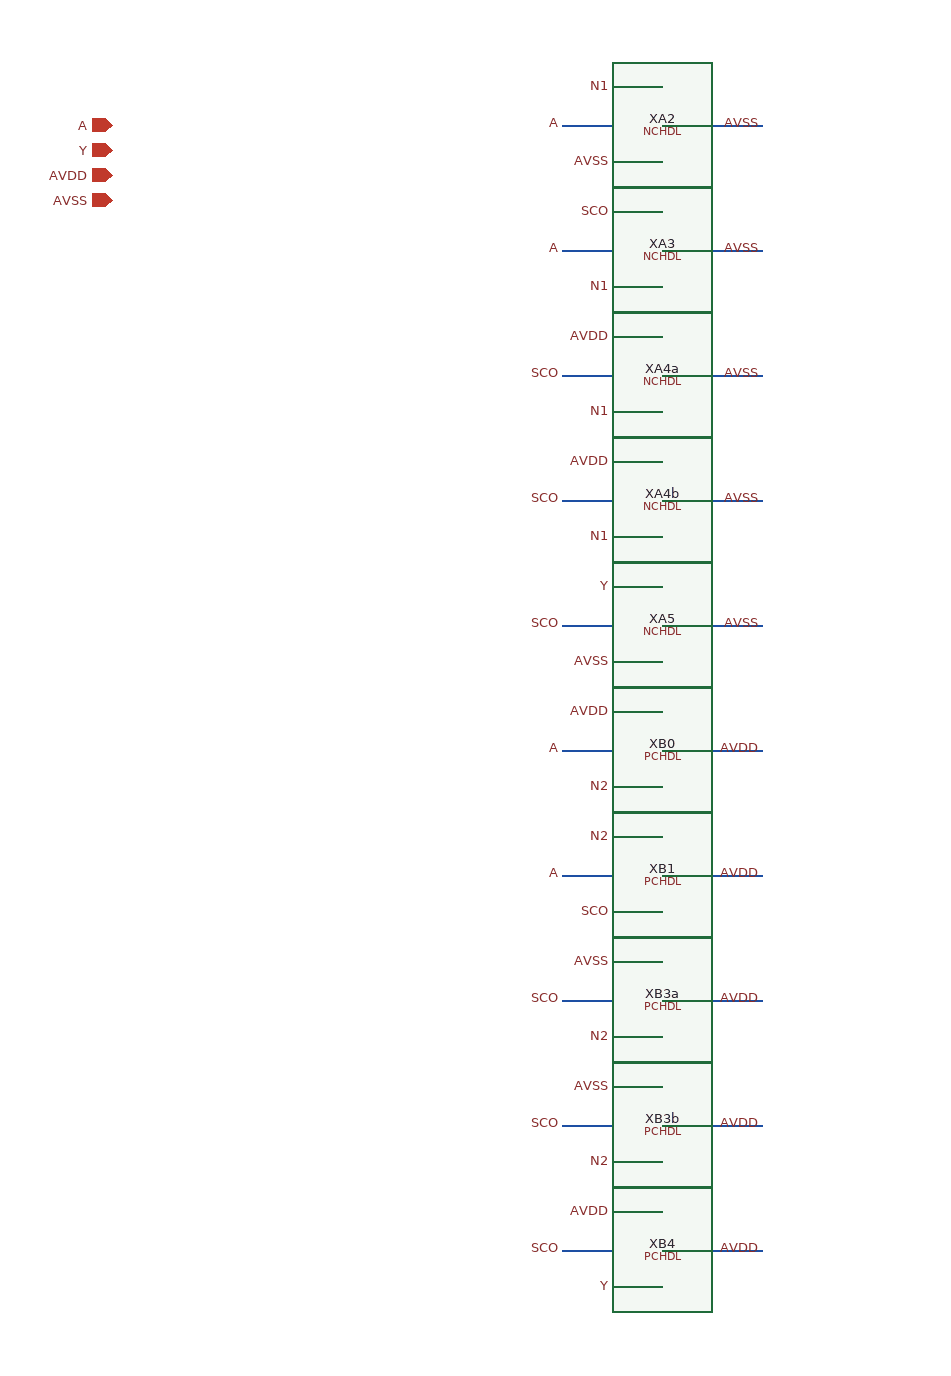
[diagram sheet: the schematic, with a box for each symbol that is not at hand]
v {xschem version=3.0.0 file_version=1.2 }
C {devices/iopin.sym} 0 0 0 0{name=p0 lab=A}
C {devices/iopin.sym} 0 20 0 0{name=p1 lab=Y}
C {devices/iopin.sym} 0 40 0 0{name=p2 lab=AVDD}
C {devices/iopin.sym} 0 60 0 0{name=p3 lab=AVSS}
C {SUN_TR_SK130NM/NCHDL.sym} 400 0 0 0 {name=XA2}
N 400.0 -30.0 440.0 -30.0{lab=N1}
C {devices/lab_pin.sym} 400.0 -30.0 0 0  {name=l0 sig_type=std_logic lab=N1 }
N 360.0 0.0 400.0 0.0{lab=A}
C {devices/lab_pin.sym} 360.0 0.0 0 0  {name=l1 sig_type=std_logic lab=A }
N 400.0 30.0 440.0 30.0{lab=AVSS}
C {devices/lab_pin.sym} 400.0 30.0 0 0  {name=l2 sig_type=std_logic lab=AVSS }
N 520.0 0.0 440.0 0.0{lab=AVSS}
C {devices/lab_pin.sym} 520.0 0.0 0 0  {name=l3 sig_type=std_logic lab=AVSS }
C {SUN_TR_SK130NM/NCHDL.sym} 400 100 0 0 {name=XA3}
N 400.0 70.0 440.0 70.0{lab=SCO}
C {devices/lab_pin.sym} 400.0 70.0 0 0  {name=l4 sig_type=std_logic lab=SCO }
N 360.0 100.0 400.0 100.0{lab=A}
C {devices/lab_pin.sym} 360.0 100.0 0 0  {name=l5 sig_type=std_logic lab=A }
N 400.0 130.0 440.0 130.0{lab=N1}
C {devices/lab_pin.sym} 400.0 130.0 0 0  {name=l6 sig_type=std_logic lab=N1 }
N 520.0 100.0 440.0 100.0{lab=AVSS}
C {devices/lab_pin.sym} 520.0 100.0 0 0  {name=l7 sig_type=std_logic lab=AVSS }
C {SUN_TR_SK130NM/NCHDL.sym} 400 200 0 0 {name=XA4a}
N 400.0 170.0 440.0 170.0{lab=AVDD}
C {devices/lab_pin.sym} 400.0 170.0 0 0  {name=l8 sig_type=std_logic lab=AVDD }
N 360.0 200.0 400.0 200.0{lab=SCO}
C {devices/lab_pin.sym} 360.0 200.0 0 0  {name=l9 sig_type=std_logic lab=SCO }
N 400.0 230.0 440.0 230.0{lab=N1}
C {devices/lab_pin.sym} 400.0 230.0 0 0  {name=l10 sig_type=std_logic lab=N1 }
N 520.0 200.0 440.0 200.0{lab=AVSS}
C {devices/lab_pin.sym} 520.0 200.0 0 0  {name=l11 sig_type=std_logic lab=AVSS }
C {SUN_TR_SK130NM/NCHDL.sym} 400 300 0 0 {name=XA4b}
N 400.0 270.0 440.0 270.0{lab=AVDD}
C {devices/lab_pin.sym} 400.0 270.0 0 0  {name=l12 sig_type=std_logic lab=AVDD }
N 360.0 300.0 400.0 300.0{lab=SCO}
C {devices/lab_pin.sym} 360.0 300.0 0 0  {name=l13 sig_type=std_logic lab=SCO }
N 400.0 330.0 440.0 330.0{lab=N1}
C {devices/lab_pin.sym} 400.0 330.0 0 0  {name=l14 sig_type=std_logic lab=N1 }
N 520.0 300.0 440.0 300.0{lab=AVSS}
C {devices/lab_pin.sym} 520.0 300.0 0 0  {name=l15 sig_type=std_logic lab=AVSS }
C {SUN_TR_SK130NM/NCHDL.sym} 400 400 0 0 {name=XA5}
N 400.0 370.0 440.0 370.0{lab=Y}
C {devices/lab_pin.sym} 400.0 370.0 0 0  {name=l16 sig_type=std_logic lab=Y }
N 360.0 400.0 400.0 400.0{lab=SCO}
C {devices/lab_pin.sym} 360.0 400.0 0 0  {name=l17 sig_type=std_logic lab=SCO }
N 400.0 430.0 440.0 430.0{lab=AVSS}
C {devices/lab_pin.sym} 400.0 430.0 0 0  {name=l18 sig_type=std_logic lab=AVSS }
N 520.0 400.0 440.0 400.0{lab=AVSS}
C {devices/lab_pin.sym} 520.0 400.0 0 0  {name=l19 sig_type=std_logic lab=AVSS }
C {SUN_TR_SK130NM/PCHDL.sym} 400 500 0 0 {name=XB0}
N 400.0 530.0 440.0 530.0{lab=N2}
C {devices/lab_pin.sym} 400.0 530.0 0 0  {name=l20 sig_type=std_logic lab=N2 }
N 360.0 500.0 400.0 500.0{lab=A}
C {devices/lab_pin.sym} 360.0 500.0 0 0  {name=l21 sig_type=std_logic lab=A }
N 400.0 470.0 440.0 470.0{lab=AVDD}
C {devices/lab_pin.sym} 400.0 470.0 0 0  {name=l22 sig_type=std_logic lab=AVDD }
N 520.0 500.0 440.0 500.0{lab=AVDD}
C {devices/lab_pin.sym} 520.0 500.0 0 0  {name=l23 sig_type=std_logic lab=AVDD }
C {SUN_TR_SK130NM/PCHDL.sym} 400 600 0 0 {name=XB1}
N 400.0 630.0 440.0 630.0{lab=SCO}
C {devices/lab_pin.sym} 400.0 630.0 0 0  {name=l24 sig_type=std_logic lab=SCO }
N 360.0 600.0 400.0 600.0{lab=A}
C {devices/lab_pin.sym} 360.0 600.0 0 0  {name=l25 sig_type=std_logic lab=A }
N 400.0 570.0 440.0 570.0{lab=N2}
C {devices/lab_pin.sym} 400.0 570.0 0 0  {name=l26 sig_type=std_logic lab=N2 }
N 520.0 600.0 440.0 600.0{lab=AVDD}
C {devices/lab_pin.sym} 520.0 600.0 0 0  {name=l27 sig_type=std_logic lab=AVDD }
C {SUN_TR_SK130NM/PCHDL.sym} 400 700 0 0 {name=XB3a}
N 400.0 730.0 440.0 730.0{lab=N2}
C {devices/lab_pin.sym} 400.0 730.0 0 0  {name=l28 sig_type=std_logic lab=N2 }
N 360.0 700.0 400.0 700.0{lab=SCO}
C {devices/lab_pin.sym} 360.0 700.0 0 0  {name=l29 sig_type=std_logic lab=SCO }
N 400.0 670.0 440.0 670.0{lab=AVSS}
C {devices/lab_pin.sym} 400.0 670.0 0 0  {name=l30 sig_type=std_logic lab=AVSS }
N 520.0 700.0 440.0 700.0{lab=AVDD}
C {devices/lab_pin.sym} 520.0 700.0 0 0  {name=l31 sig_type=std_logic lab=AVDD }
C {SUN_TR_SK130NM/PCHDL.sym} 400 800 0 0 {name=XB3b}
N 400.0 830.0 440.0 830.0{lab=N2}
C {devices/lab_pin.sym} 400.0 830.0 0 0  {name=l32 sig_type=std_logic lab=N2 }
N 360.0 800.0 400.0 800.0{lab=SCO}
C {devices/lab_pin.sym} 360.0 800.0 0 0  {name=l33 sig_type=std_logic lab=SCO }
N 400.0 770.0 440.0 770.0{lab=AVSS}
C {devices/lab_pin.sym} 400.0 770.0 0 0  {name=l34 sig_type=std_logic lab=AVSS }
N 520.0 800.0 440.0 800.0{lab=AVDD}
C {devices/lab_pin.sym} 520.0 800.0 0 0  {name=l35 sig_type=std_logic lab=AVDD }
C {SUN_TR_SK130NM/PCHDL.sym} 400 900 0 0 {name=XB4}
N 400.0 930.0 440.0 930.0{lab=Y}
C {devices/lab_pin.sym} 400.0 930.0 0 0  {name=l36 sig_type=std_logic lab=Y }
N 360.0 900.0 400.0 900.0{lab=SCO}
C {devices/lab_pin.sym} 360.0 900.0 0 0  {name=l37 sig_type=std_logic lab=SCO }
N 400.0 870.0 440.0 870.0{lab=AVDD}
C {devices/lab_pin.sym} 400.0 870.0 0 0  {name=l38 sig_type=std_logic lab=AVDD }
N 520.0 900.0 440.0 900.0{lab=AVDD}
C {devices/lab_pin.sym} 520.0 900.0 0 0  {name=l39 sig_type=std_logic lab=AVDD }
